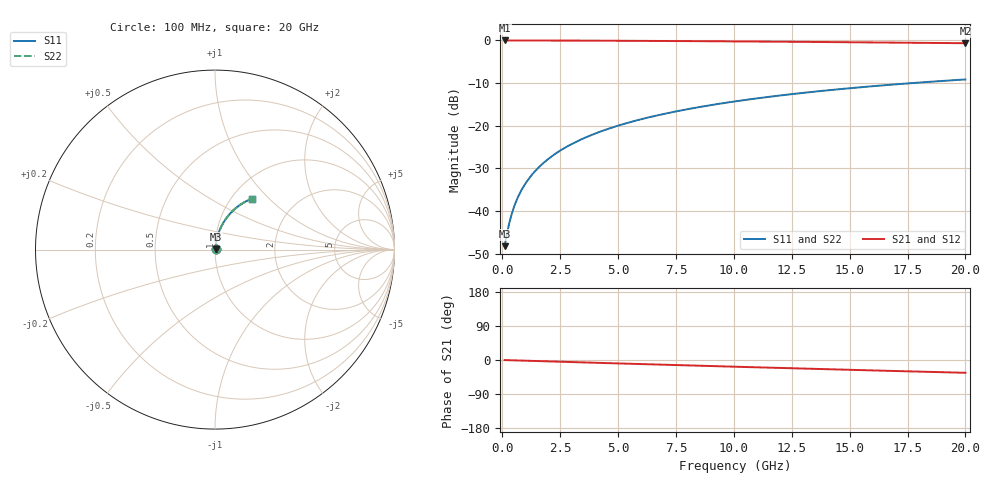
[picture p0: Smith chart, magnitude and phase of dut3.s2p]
! Touchstone file exported from HFSS 2026.1.0
!  File:  C:/ffzhzh/LocalFiles/Ansys_Project_Files/temp_test_TMRDL_3_1782906810_42304.aedt
!  Generated:  07:54:43 PM Jul  1, 2026
!  Design:  TMRDL
!  Project:  temp_test_TMRDL_3_1782906810_42304
! Variables:
!  h_bsmrdl = 2um
!  h_ox = 20um
!  h_rdl = 5um
!  h_sub = 80um
!  h_tmrdl = 4.94um
!  h_tsv = 80um
!  h_via = 3um
!  l_bsmrdl = 300um
!  l_sub = 876.44um
!  l_tmrdl = 476.44um
!  m_sub = 200um
!  pitch = 34.03um
!  r_tsv = 6um
!  s_tmrdl = 10um
!  w_bsmrdl = 18um
!  w_sub = 500um
!  w_tmrdl = 10.71um
!  x_tsv_center1 = 481.795um
!  x_tsv_center2 = 799.795um
!  x_tsv_center3 = 1286.945um
!  x_tsv_center4 = 1604.945um
!  x_tsv_center5 = 2092.095um
!  x_tsv_center6 = 2410.095um
# GHz S MA R 50.000000
! Terminal data exported
! Port[1] = TM_RDL1_1_T1
! Port[2] = TM_RDL1_1_T2
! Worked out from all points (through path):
!   200 points, 100 MHz to 20 GHz, reference 50 ohm
!   highest |S21| = -0.03 dB at 100 MHz (marker M1); lowest = -0.7 dB at 20 GHz (marker M2)
!   group delay of S21, straight-line fit = 4.69 ps
!   lowest |S11| = -48.2 dB at 100 MHz (marker M3), VSWR 1.01, Z = 50.3 + j0.215 ohm
!   |S11| at or under -10 dB: start of sweep to 17.73 GHz
!   |S22| runs from -48.2 to -9.2 dB; largest |S21 - S12| = 2e-15
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0.1  0.003883 33.4  0.9968 -0.2  0.9968 -0.2  0.003883 33.4
! Gamma 0 0 0 0
! Port Impedance 50 0 50 0
0.2  0.005392 52.1  0.9967 -0.4  0.9967 -0.4  0.005392 52.1
0.3  0.007205 61.7  0.9966 -0.6  0.9966 -0.6  0.007206 61.7
0.4  0.009122 67.2  0.9965 -0.7  0.9965 -0.7  0.009122 67.2
0.5  0.01108 70.6  0.9964 -0.9  0.9964 -0.9  0.01108 70.6
0.6  0.01305 73.0  0.9964 -1.1  0.9964 -1.1  0.01305 73.0
0.8  0.01702 76.0  0.9962 -1.5  0.9962 -1.5  0.01702 76.0
1.1  0.02301 78.4  0.996 -2.0  0.996 -2.0  0.02302 78.4
1.5  0.03104 79.9  0.9956 -2.8  0.9956 -2.8  0.03104 79.9
1.8  0.03707 80.3  0.9952 -3.3  0.9952 -3.3  0.03707 80.3
2.1  0.04309 80.5  0.9949 -3.8  0.9949 -3.8  0.04309 80.5
2.7  0.05509 80.3  0.9939 -4.9  0.9939 -4.9  0.05509 80.3
3.5  0.07094 79.5  0.9924 -6.4  0.9924 -6.4  0.07094 79.5
4.2  0.08466 78.6  0.9908 -7.6  0.9908 -7.6  0.08466 78.6
5  0.1001 77.4  0.9888 -9.0  0.9888 -9.0  0.1001 77.4
5.9  0.1173 76.1  0.9863 -10.6  0.9863 -10.6  0.1173 76.1
6.8  0.1341 74.7  0.9836 -12.2  0.9836 -12.2  0.1341 74.7
8.3  0.1616 72.3  0.9785 -14.8  0.9785 -14.8  0.1616 72.3
10.1  0.1935 69.4  0.9718 -17.8  0.9718 -17.8  0.1935 69.4
13.4  0.2493 64.3  0.9579 -23.3  0.9579 -23.3  0.2493 64.3
16.7  0.301 59.2  0.9421 -28.6  0.9421 -28.6  0.301 59.2
20  0.3484 54.3  0.9251 -33.8  0.9251 -33.8  0.3484 54.2
